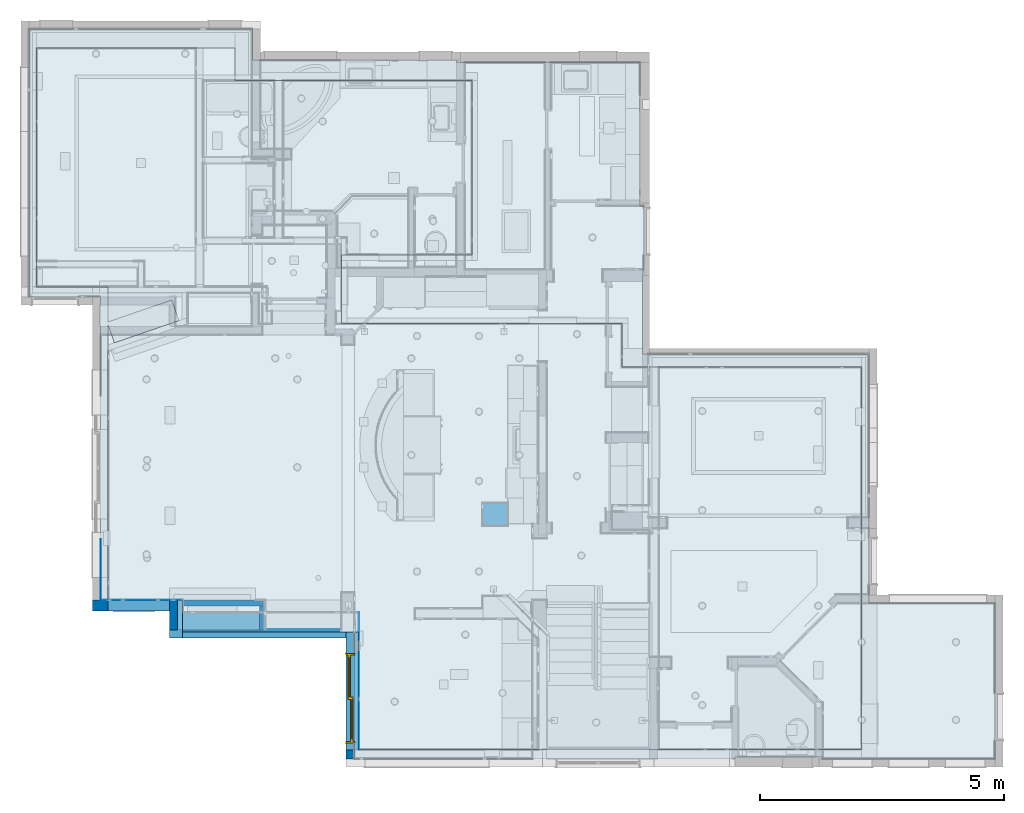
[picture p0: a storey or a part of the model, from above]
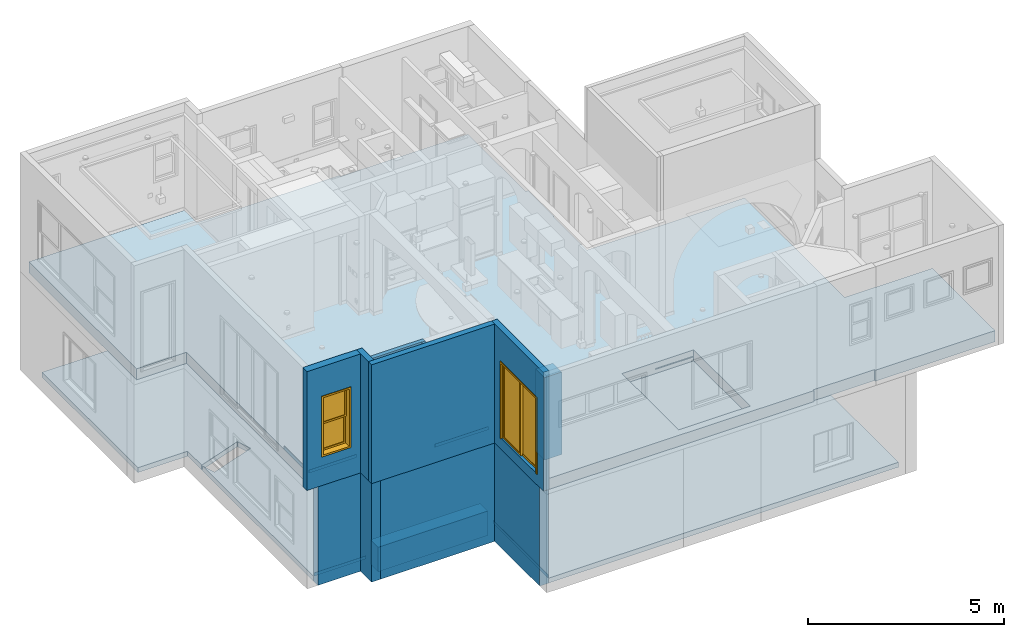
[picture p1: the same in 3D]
Properties of the parts of a building model (IFC2X3), part 1 of 2

# File
Description: ViewDefinition [CoordinationView_V2.0], RevitIdentifiers [ContentGUID: , VersionGUID: 23c3c518-4028-4475-b060-c0a772637db6, NumberOfSaves: 229], CoordinateReference [CoordinateBase: Shared Coordinates, ProjectSite: Internal]
File name: Global_Backcountry.ifc
Time: 2026-02-05T12:27:19+05:30
Written by: ODA SDAI 22.12
Made in: Autodesk Revit 23.1.80.30 (ENG) - IFC 23.4.1.0

# IfcProject, Project Number
LongName: Project Name; Phase: Project Status

# IfcSite, Default
RefLatitude: 42, 21, 30, 344238; RefLongitude: -71, -3, -35, -194702; RefElevation: 0 ft

# IfcBuilding
Pset_BuildingCommon - NumberOfStoreys: 1

# IfcBuildingStorey: Level:1/4" Head (2)
Pset_AirSideSystemInformation - sets with these values: 2
Name | LongName = Name | Elevation (ft)
First floor | First floor | 0
Third floor | Third floor | 27.1667

# IfcBuildingElementProxy: C_ Oven-Single1:C_ Oven-Single 2, C_ Oven-Single1:C_ Oven-Single 2:1988304
In: First floor
Type - Material: Default New Material
Classification: E1090320 Food Service - Appliances & Equipment (Uniformat)
Pset_BuildingElementProxyCommon - Reference: C_ Oven-Single 2; sets with these values: 2

# IfcBuildingElementProxy: C_ Oven-Single1:C_ Oven-Single 3, C_ Oven-Single1:C_ Oven-Single 3:1993433
In: First floor
Type - Material: Default New Material
Classification: E1090320 Food Service - Appliances & Equipment (Uniformat)
Pset_BuildingElementProxyCommon - Reference: C_ Oven-Single 3; sets with these values: 2

# IfcBuildingElementProxy: C_Ceiling Plinth:C_Ceiling Plinth (19)
In: First floor
Type - Material: Default New Material
Pset_BuildingElementProxyCommon - Reference: C_Ceiling Plinth; sets with these values: 2
Name (C_Ceiling Plinth:C_Ceiling Plinth:...)
1970175
1970182
1970189
1970195
1970569
1970576
1970590
1970596
1973254
1973261
1973268
1973275
1973369
1973376
1973383
1973389
1978767
1978790
2012152

# IfcBuildingElementProxy: C_Kitchen Hood:C_Kitchen Hood 2, C_Kitchen Hood:C_Kitchen Hood 2:1905955
In: First floor
Type - Material: Default New Material
Classification: E1090320 Food Service - Appliances & Equipment (Uniformat)
Pset_BuildingElementProxyCommon - Reference: C_Kitchen Hood 2; sets with these values: 2

# IfcBuildingElementProxy: C_Oven-Microwave1:C_Oven-Microwave 2, C_Oven-Microwave1:C_Oven-Microwave 2:1991351
In: First floor
Type - Material: Default New Material
Classification: E1090320 Food Service - Appliances & Equipment (Uniformat)
Pset_BuildingElementProxyCommon - Reference: C_Oven-Microwave 2; sets with these values: 2

# IfcBuildingElementProxy: C_Refrigerator:30" x 24" LH, C_Refrigerator:30" x 24" LH:1872095
In: First floor
Type - Material: Default New Material, Metal - Chrome
Classification: E1090400 Residential Equipment (Uniformat)
Pset_BuildingElementProxyCommon - Reference: 30" x 24" LH; sets with these values: 2

# IfcBuildingElementProxy: C_Wall Board:C_Wall Board (6)
In: First floor
Type - Material: Default New Material
Pset_BuildingElementProxyCommon - Reference: C_Wall Board; sets with these values: 2
Name (C_Wall Board:C_Wall Board:...)
1997285
1997406
1997414
1997422
1997430
1997438

# IfcBuildingElementProxy: Generic Models 10:Generic Models 10, Generic Models 10:Generic Models 10:1850394
In: First floor
Type - Material: Default New Material
Pset_BuildingElementProxyCommon - Reference: Generic Models 10; sets with these values: 2

# IfcBuildingElementProxy: Generic Models 11:Generic Models 11, Generic Models 11:Generic Models 11:1826560
In: First floor
Type - Material: Default New Material
Pset_BuildingElementProxyCommon - Reference: Generic Models 11; sets with these values: 2

# IfcBuildingElementProxy: Generic Models 14:Generic Models 14, Generic Models 14:Generic Models 14:2007178
In: First floor
Type - Material: Default New Material
Pset_BuildingElementProxyCommon - Reference: Generic Models 14; sets with these values: 2

# IfcBuildingElementProxy: Generic Models 15:Generic Models 4, Generic Models 15:Generic Models 4:1890981
In: First floor
Type - Material: Default New Material
Pset_BuildingElementProxyCommon - Reference: Generic Models 4; sets with these values: 2

# IfcBuildingElementProxy: Generic Models 16:Generic Models 16, Generic Models 16:Generic Models 16:1832114
In: First floor
Type - Material: Default New Material, Glass
Pset_BuildingElementProxyCommon - Reference: Generic Models 16; sets with these values: 2

# IfcBuildingElementProxy: Generic Models 18:Generic Models 18, Generic Models 18:Generic Models 18:2007954
In: First floor
Type - Material: Default New Material
Pset_BuildingElementProxyCommon - Reference: Generic Models 18; sets with these values: 2

# IfcBuildingElementProxy: Generic Models 22:Generic Models 22, Generic Models 22:Generic Models 22:1832233
In: First floor
Type - Material: Default New Material
Pset_BuildingElementProxyCommon - Reference: Generic Models 22; sets with these values: 2

# IfcBuildingElementProxy: Generic Models 23:Generic Models 16, Generic Models 23:Generic Models 16:1821259
In: First floor
Type - Material: Default New Material
Pset_BuildingElementProxyCommon - Reference: Generic Models 16; sets with these values: 2

# IfcBuildingElementProxy: Generic Models 24:Generic Models 24, Generic Models 24:Generic Models 24:1832501
In: First floor
Type - Material: Default New Material
Pset_BuildingElementProxyCommon - Reference: Generic Models 24; sets with these values: 2

# IfcBuildingElementProxy: Generic Models 25:Generic Models 23, Generic Models 25:Generic Models 23:1834578
In: First floor
Type - Material: Default New Material
Pset_BuildingElementProxyCommon - Reference: Generic Models 23; sets with these values: 2

# IfcBuildingElementProxy: Generic Models 30:Generic Models 30, Generic Models 30:Generic Models 30:2006890
In: First floor
Type - Material: Default New Material
Pset_BuildingElementProxyCommon - Reference: Generic Models 30; sets with these values: 2

# IfcBuildingElementProxy: Generic Models 38:Generic Models 38, Generic Models 38:Generic Models 38:1893735
In: First floor
Type - Material: Default New Material
Pset_BuildingElementProxyCommon - Reference: Generic Models 38; sets with these values: 2

# IfcBuildingElementProxy: Generic Models 4:Generic Models 3, Generic Models 4:Generic Models 3:1832471
In: First floor
Type - Material: Glass
Pset_BuildingElementProxyCommon - Reference: Generic Models 3; sets with these values: 2

# IfcBuildingElementProxy: Generic Models 52:Generic Models 52, Generic Models 52:Generic Models 52:1856574
In: First floor
Type - Material: Default New Material
Pset_BuildingElementProxyCommon - Reference: Generic Models 52; sets with these values: 2

# IfcBuildingElementProxy: Generic Models 59:Generic Models 59, Generic Models 59:Generic Models 59:1832529
In: First floor
Type - Material: Default New Material
Pset_BuildingElementProxyCommon - Reference: Generic Models 59; sets with these values: 2

# IfcBuildingElementProxy: Generic Models 60:Generic Models 59, Generic Models 60:Generic Models 59:1832543
In: First floor
Type - Material: Default New Material
Pset_BuildingElementProxyCommon - Reference: Generic Models 59; sets with these values: 2

# IfcBuildingElementProxy: Generic Models 61:Generic Models 61, Generic Models 61:Generic Models 61:1834870
In: First floor
Type - Material: Default New Material
Pset_BuildingElementProxyCommon - Reference: Generic Models 61; sets with these values: 2

# IfcBuildingElementProxy: Generic Models 66:Generic Models 66, Generic Models 66:Generic Models 66:1836599
In: First floor
Type - Material: Default New Material
Pset_BuildingElementProxyCommon - Reference: Generic Models 66; sets with these values: 2

# IfcBuildingElementProxy: Generic Models 67:Generic Models 67, Generic Models 67:Generic Models 67:1890026
In: First floor
Type - Material: Default New Material
Pset_BuildingElementProxyCommon - Reference: Generic Models 67; sets with these values: 2

# IfcBuildingElementProxy: Generic Models 68:Generic Models 68, Generic Models 68:Generic Models 68:1878332
In: First floor
Type - Material: Default New Material
Pset_BuildingElementProxyCommon - Reference: Generic Models 68; sets with these values: 2

# IfcBuildingElementProxy: Generic Models 7:Generic Models 7, Generic Models 7:Generic Models 7:1826515
In: First floor
Type - Material: Default New Material
Pset_BuildingElementProxyCommon - Reference: Generic Models 7; sets with these values: 2

# IfcBuildingElementProxy: Generic Models 8:Generic Models 8, Generic Models 8:Generic Models 8:1850366
In: First floor
Type - Material: Default New Material
Pset_BuildingElementProxyCommon - Reference: Generic Models 8; sets with these values: 2

# IfcBuildingElementProxy: Generic Models 9:Generic Models 9, Generic Models 9:Generic Models 9:1850380
In: First floor
Type - Material: Default New Material
Pset_BuildingElementProxyCommon - Reference: Generic Models 9; sets with these values: 2

# IfcBuildingElementProxy: Specialty Equipment 1:Specialty Equipment 1, Specialty Equipment 1:Specialty Equipment 1:1830147
In: First floor
Type - Material: Default New Material
Pset_BuildingElementProxyCommon - Reference: Specialty Equipment 1; sets with these values: 2

# IfcBuildingElementProxy: Specialty Equipment_1:Specialty Equipment_1 (10)
In: First floor
Type - Material: Default New Material
Pset_BuildingElementProxyCommon - Reference: Specialty Equipment_1; sets with these values: 2
Name (Specialty Equipment_1:Specialty Equipment_1:...)
1832861
1832868
1832869
1832870
1832871
1832872
1832873
1832874
1832875
1832876

# IfcBuildingElementProxy: Specialty Equipment_2:Specialty Equipment_2, Specialty Equipment_2:Specialty Equipment_2:1875328
In: First floor
Type - Material: Default New Material
Pset_BuildingElementProxyCommon - Reference: Specialty Equipment_2; sets with these values: 2

# IfcBuildingElementProxy: Specialty Equipment_4:Specialty Equipment_4 (6)
In: First floor
Type - Material: Default New Material
Pset_BuildingElementProxyCommon - Reference: Specialty Equipment_4; sets with these values: 2
Name (Specialty Equipment_4:Specialty Equipment_4:...)
1834781
1834782
1834783
1834784
1834785
1834786

# IfcBuildingElementProxy: Wall void 1 :Wall void 1, Wall void 1 :Wall void 1:1623852
In: First floor
Type - Material: Default New Material
Pset_BuildingElementProxyCommon - Reference: Wall void 1; sets with these values: 2

# IfcBuildingElementProxy: switch 15:switch 15 (9)
In: First floor
Type - Material: Default New Material
Pset_BuildingElementProxyCommon - Reference: switch 15; sets with these values: 2
Name (switch 15:switch 15:...)
1977471
1978495
1978551
1980305
1980369
1980450
1999142
1999231
1999335

# IfcBuildingElementProxy: switch 1:switch 1 (35)
In: First floor
Type - Material: Default New Material
Pset_BuildingElementProxyCommon - Reference: switch 1; sets with these values: 2
Name (switch 1:switch 1:...)
1818208
1818322
1830585
1830647
1833578
1833643
1835219
1835559
1836760
1844375
1849006
1849609
1849780
1854866
1854953
1856204
1863419
1863629
1863692
1866938
1867050
1890236
1890352
1890636
1893331
1898502
1898551
1898586
1898853
1900308
1900660
1900951
1901115
1902148
1902609

# IfcBuildingElementProxy: switch 20:switch 20, switch 20:switch 20:1898083
In: First floor
Type - Material: Default New Material
Pset_BuildingElementProxyCommon - Reference: switch 20; sets with these values: 2

# IfcBuildingElementProxy: switch 22:switch 22 (8)
In: First floor
Type - Material: Default New Material
Pset_BuildingElementProxyCommon - Reference: switch 22; sets with these values: 2
Name (switch 22:switch 22:...)
1829911
1833335
1836847
1857173
1861944
1863794
1878393
1899789

# IfcBuildingElementProxy: switch 24:switch 24 (4)
In: First floor
Type - Material: Default New Material
Pset_BuildingElementProxyCommon - Reference: switch 24; sets with these values: 2
Name (switch 24:switch 24:...)
1862058
1862175
1867309
1868340

# IfcBuildingElementProxy: switch 2:switch 2 (2)
In: First floor
Type - Material: Default New Material
Pset_BuildingElementProxyCommon - Reference: switch 2; sets with these values: 2
Name (switch 2:switch 2:...)
1890583
1890810

# IfcBuildingElementProxy: switch 3:switch 3 (10)
In: First floor
Type - Material: Default New Material
Pset_BuildingElementProxyCommon - Reference: switch 3; sets with these values: 2
Name (switch 3:switch 3:...)
1826171
1830789
1835476
1855795
1883014
1887228
1899510
1900826
1902023
1902519

# IfcBuildingElementProxy: switch 4:switch 4 (50)
In: First floor
Type - Material: Default New Material
Pset_BuildingElementProxyCommon - Reference: switch 4; sets with these values: 2
Name (switch 4:switch 4:...)
1818084
1818843
1825703
1830070
1832985
1833240
1833453
1833995
1834143
1835044
1836454
1836673
1844247
1849133
1856108
1861414
1862980
1863063
1863317
1864811
1864893
1883154
1888046
1890142
1890323
1890444
1890517
1890704
1892060
1892179
1893450
1893569
1893621
1893776
1893854
1898173
1899133
1899192
1899691
1899955
1900022
1900478
1900567
1901199
1901303
1901771
1901831
1901936
1902272
2013332

# IfcBuildingElementProxy: switch 6:switch 6 (14)
In: First floor
Type - Material: Default New Material
Pset_BuildingElementProxyCommon - Reference: switch 6; sets with these values: 2
Name (switch 6:switch 6:...)
1818533
1818772
1833104
1833717
1833870
1837094
1837330
1855957
1866779
1888173
1889682
1900150
1905417
1917963

# IfcColumn: M_Rectangular Column:475 x 610mm, M_Rectangular Column:475 x 610mm:2013331
In: First floor
Type - PredefinedType: COLUMN; Material: Default New Material
Pset_ColumnCommon - IsExternal: no; Reference: 475 x 610mm
Pset_QuantityTakeOff - Reference: 475 x 610mm; sets with these values: 2

# IfcCovering: Compound Ceiling:Ceiling_1.5", Compound Ceiling:Ceiling_1.5":1623691
In: First floor
Type - PredefinedType: CEILING
Type - Pset_CoveringCommon - TotalThickness: 0.125 ft
Classification: C3030210 Suspended Ceilings - Acoustical (Uniformat); Material: Default New Material 0.125 ft
Pset_CoveringCommon - Reference: Ceiling_1.5"; sets with these values: 2

# IfcCovering: Compound Ceiling:Ceiling_1.5" 1, Compound Ceiling:Ceiling_1.5" 1:1623705
In: First floor
Type - PredefinedType: CEILING
Type - Pset_CoveringCommon - TotalThickness: 0.125 ft
Classification: C3030210 Suspended Ceilings - Acoustical (Uniformat); Material: Default New Material 0.125 ft
Pset_CoveringCommon - Reference: Ceiling_1.5" 1; sets with these values: 2

# IfcCovering: Compound Ceiling:Ceiling_12", Compound Ceiling:Ceiling_12":1623663
In: First floor
Type - PredefinedType: CEILING
Type - Pset_CoveringCommon - TotalThickness: 1 ft
Classification: C3030210 Suspended Ceilings - Acoustical (Uniformat); Material: Default New Material 1 ft
Pset_CoveringCommon - Reference: Ceiling_12"; sets with these values: 2

# IfcCovering: Compound Ceiling:Ceiling_13.5", Compound Ceiling:Ceiling_13.5":1623320
In: First floor
Type - PredefinedType: CEILING
Type - Pset_CoveringCommon - TotalThickness: 1.125 ft
Classification: C3030210 Suspended Ceilings - Acoustical (Uniformat); Material: Default New Material 1.125 ft
Pset_CoveringCommon - Reference: Ceiling_13.5"; sets with these values: 2

# IfcCovering: Compound Ceiling:Ceiling_14", Compound Ceiling:Ceiling_14":1623614
In: First floor
Type - PredefinedType: CEILING
Type - Pset_CoveringCommon - TotalThickness: 1.16667 ft
Classification: C3030210 Suspended Ceilings - Acoustical (Uniformat); Material: Default New Material 1.16667 ft
Pset_CoveringCommon - Reference: Ceiling_14"; sets with these values: 2

# IfcCovering: Compound Ceiling:Ceiling_2", Compound Ceiling:Ceiling_2":1623593
In: First floor
Type - PredefinedType: CEILING
Type - Pset_CoveringCommon - TotalThickness: 0.166667 ft
Classification: C3030210 Suspended Ceilings - Acoustical (Uniformat); Material: Default New Material 0.166667 ft
Pset_CoveringCommon - Reference: Ceiling_2"; sets with these values: 2

# IfcCovering: Compound Ceiling:Ceiling_5.25", Compound Ceiling:Ceiling_5.25":1623642
In: First floor
Type - PredefinedType: CEILING
Type - Pset_CoveringCommon - TotalThickness: 0.4375 ft
Classification: C3030210 Suspended Ceilings - Acoustical (Uniformat); Material: Default New Material 0.4375 ft
Pset_CoveringCommon - Reference: Ceiling_5.25"; sets with these values: 2

# IfcCovering: Compound Ceiling:Ceiling_6" (6)
In: First floor
Type - PredefinedType: CEILING
Type - Pset_CoveringCommon - TotalThickness: 0.5 ft
Classification: C3030210 Suspended Ceilings - Acoustical (Uniformat); Material: Default New Material 0.5 ft
Pset_CoveringCommon - Reference: Ceiling_6"; sets with these values: 2
Name (Compound Ceiling:Ceiling_6":...)
1623496
1623539
1623550
1843769
1878108
1887144

# IfcDistributionPort (54)
Description: Flow; FlowDirection: SOURCEANDSINK
Name
Port_1757719_1
Port_1759716_1
Port_1759780_1
Port_1759781_1
Port_1759806_1
Port_1759857_1
Port_1760309_1
Port_1760412_1
Port_1760436_1
Port_1760555_1
Port_1760695_1
Port_1760920_1
Port_1760941_1
Port_1760962_1
Port_1761019_1
Port_1761040_1
Port_1761170_1
Port_1761231_1
Port_1761579_1
Port_1761622_1
Port_1761695_1
Port_1761776_1
Port_1761873_1
Port_1761934_1
Port_1762098_1
Port_1764306_1
Port_1764405_1
Port_1764552_1
Port_1764702_1
Port_1764775_1
Port_1764865_1
Port_1764925_1
Port_1764992_1
Port_1765164_1
Port_1765362_1
Port_1765494_1
Port_1765568_1
Port_1765795_1
Port_1765961_1
Port_1766023_1
Port_1766063_1
Port_1766123_1
Port_1766230_1
Port_1766277_1
Port_1766412_1
Port_1766564_1
Port_1766834_1
Port_1766973_1
Port_1767096_1
Port_1767216_1
Port_1767358_1
Port_1988304_1
Port_1991351_1
Port_1993433_1

# IfcDoor: C_Double Door Glass:4'-8" X 8'-0", C_Double Door Glass:4'-8" X 8'-0":1623472
In: First floor
Type - OperationType: DOUBLE_DOOR_SINGLE_SWING_OPPOSITE_RIGHT; ParameterTakesPrecedence: no; Sizeable: no; Material: Default New Material, Glass
Type - C_Double Door Glass:4'-8" X 8'-0":1623472:1 - PanelOperation: SWINGING
OverallHeight: 8.08333 ft; OverallWidth: 4.83333 ft
Pset_DoorCommon - Reference: 4'-8" X 8'-0"; IsExternal: no
Pset_QuantityTakeOff - Reference: 4'-8" X 8'-0"

# IfcDoor: C_Double Door Glass:4'-8" X 8'-2", C_Double Door Glass:4'-8" X 8'-2":1623377
In: First floor
Type - OperationType: DOUBLE_DOOR_SINGLE_SWING_OPPOSITE_LEFT; ParameterTakesPrecedence: no; Sizeable: no; Material: Default New Material, Glass
Type - C_Double Door Glass:4'-8" X 8'-2":1623377:1 - PanelOperation: SWINGING
OverallHeight: 8.25 ft; OverallWidth: 4.83333 ft
Pset_DoorCommon - IsExternal: no; Reference: 4'-8" X 8'-2"
Pset_QuantityTakeOff - Reference: 4'-8" X 8'-2"

# IfcDoor: C_Single Door Glass:3'-0" X 8'-0", C_Single Door Glass:3'-0" X 8'-0":1623399
In: First floor
Type - OperationType: SINGLE_SWING_RIGHT; ParameterTakesPrecedence: no; Sizeable: no; Material: Glass, Default New Material
Type - C_Single Door Glass:3'-0" X 8'-0":1623399:1 - PanelOperation: SWINGING
OverallHeight: 8.08333 ft; OverallWidth: 3.16667 ft
Pset_DoorCommon - IsExternal: no; Reference: 3'-0" X 8'-0"
Pset_QuantityTakeOff - Reference: 3'-0" X 8'-0"

# IfcDoor: C_Single Door Glass:3'-0" X 8'-0", C_Single Door Glass:3'-0" X 8'-0":1623471
In: First floor
Type - OperationType: SINGLE_SWING_RIGHT; ParameterTakesPrecedence: no; Sizeable: no; Material: Glass, Default New Material
Type - C_Single Door Glass:3'-0" X 8'-0":1623471:1 - PanelOperation: SWINGING
OverallHeight: 8.08333 ft; OverallWidth: 3.16667 ft
Pset_DoorCommon - IsExternal: no; Reference: 3'-0" X 8'-0"
Pset_QuantityTakeOff - Reference: 3'-0" X 8'-0"

# IfcDoor: C_Single Door:2'-0" X 8'-0", C_Single Door:2'-0" X 8'-0":1623488
In: First floor
Type - OperationType: SINGLE_SWING_LEFT; ParameterTakesPrecedence: no; Sizeable: no; Material: Default New Material
Type - C_Single Door:2'-0" X 8'-0":1623488:1 - PanelOperation: SWINGING
OverallHeight: 8.08333 ft; OverallWidth: 2.16667 ft
Pset_DoorCommon - Reference: 2'-0" X 8'-0"; IsExternal: no
Pset_QuantityTakeOff - Reference: 2'-0" X 8'-0"

# IfcDoor: C_Single Door:2'-4" X 8'-0" (4)
In: First floor
Type - OperationType: SINGLE_SWING_RIGHT; ParameterTakesPrecedence: no; Sizeable: no; Material: Default New Material
Type - C_Single Door:2'-4" X 8'-0":1623375:1 - PanelOperation: SWINGING
OverallHeight: 8.08333 ft; OverallWidth: 2.5 ft
Pset_DoorCommon - IsExternal: no; Reference: 2'-4" X 8'-0"
Pset_QuantityTakeOff - Reference: 2'-4" X 8'-0"
Name (C_Single Door:2'-4" X 8'-0":...)
1623375
1623376
1623473
1623474

# IfcDoor: C_Single Door:2'-4" X 8'-0", C_Single Door:2'-4" X 8'-0":1623401
In: First floor
Type - OperationType: SINGLE_SWING_RIGHT; ParameterTakesPrecedence: no; Sizeable: no; Material: Default New Material
Type - C_Single Door:2'-4" X 8'-0":1623401:1 - PanelOperation: SWINGING
OverallHeight: 8.08333 ft; OverallWidth: 2.5 ft
Pset_DoorCommon - IsExternal: no; Reference: 2'-4" X 8'-0"
Pset_QuantityTakeOff - Reference: 2'-4" X 8'-0"

# IfcDoor: C_Single Door:2'-4" X 8'-2", C_Single Door:2'-4" X 8'-2":1623386
In: First floor
Type - OperationType: SINGLE_SWING_LEFT; ParameterTakesPrecedence: no; Sizeable: no; Material: Default New Material
Type - C_Single Door:2'-4" X 8'-2":1623386:1 - PanelOperation: SWINGING
OverallHeight: 8.25 ft; OverallWidth: 2.5 ft
Pset_DoorCommon - IsExternal: no; Reference: 2'-4" X 8'-2"
Pset_QuantityTakeOff - Reference: 2'-4" X 8'-2"

# IfcDoor: C_Single Door:2'-4" X 8'-2" (3)
In: First floor
Type - OperationType: SINGLE_SWING_RIGHT; ParameterTakesPrecedence: no; Sizeable: no; Material: Default New Material
Type - C_Single Door:2'-4" X 8'-2":1623384:1 - PanelOperation: SWINGING
OverallHeight: 8.25 ft; OverallWidth: 2.5 ft
Pset_DoorCommon - IsExternal: no; Reference: 2'-4" X 8'-2"
Pset_QuantityTakeOff - Reference: 2'-4" X 8'-2"
Name (C_Single Door:2'-4" X 8'-2":...)
1623384
1623387
1623388

# IfcDoor: C_Single Door:2'-6" X 6'-8", C_Single Door:2'-6" X 6'-8":1623378
In: First floor
Type - OperationType: SINGLE_SWING_LEFT; ParameterTakesPrecedence: no; Sizeable: no; Material: Default New Material
Type - C_Single Door:2'-6" X 6'-8":1623378:1 - PanelOperation: SWINGING
OverallHeight: 6.75 ft; OverallWidth: 2.66667 ft
Pset_DoorCommon - IsExternal: no; Reference: 2'-6" X 6'-8"
Pset_QuantityTakeOff - Reference: 2'-6" X 6'-8"

# IfcDoor: C_Single Door:2'-6" X 8'-0" (2)
In: First floor
Type - OperationType: SINGLE_SWING_LEFT; ParameterTakesPrecedence: no; Sizeable: no; Material: Default New Material
Type - C_Single Door:2'-6" X 8'-0":1623370:1 - PanelOperation: SWINGING
OverallHeight: 8.08333 ft; OverallWidth: 2.66667 ft
Pset_DoorCommon - IsExternal: no; Reference: 2'-6" X 8'-0"
Pset_QuantityTakeOff - Reference: 2'-6" X 8'-0"
Name (C_Single Door:2'-6" X 8'-0":...)
1623370
1623380

# IfcDoor: C_Single Door:2'-6" X 8'-0", C_Single Door:2'-6" X 8'-0":1623374
In: First floor
Type - OperationType: SINGLE_SWING_LEFT; ParameterTakesPrecedence: no; Sizeable: no; Material: Default New Material
Type - C_Single Door:2'-6" X 8'-0":1623374:1 - PanelOperation: SWINGING
OverallHeight: 8.08333 ft; OverallWidth: 2.66667 ft
Pset_DoorCommon - IsExternal: no; Reference: 2'-6" X 8'-0"
Pset_QuantityTakeOff - Reference: 2'-6" X 8'-0"

# IfcDoor: C_Single Door:2'-6" X 8'-0", C_Single Door:2'-6" X 8'-0":1623393
In: First floor
Type - OperationType: SINGLE_SWING_LEFT; ParameterTakesPrecedence: no; Sizeable: no; Material: Default New Material
Type - C_Single Door:2'-6" X 8'-0":1623393:1 - PanelOperation: SWINGING
OverallHeight: 8.08333 ft; OverallWidth: 2.66667 ft
Pset_DoorCommon - IsExternal: no; Reference: 2'-6" X 8'-0"
Pset_QuantityTakeOff - Reference: 2'-6" X 8'-0"

# IfcDoor: C_Single Door:2'-6" X 8'-2", C_Single Door:2'-6" X 8'-2":1623385
In: First floor
Type - OperationType: SINGLE_SWING_RIGHT; ParameterTakesPrecedence: no; Sizeable: no; Material: Default New Material
Type - C_Single Door:2'-6" X 8'-2":1623385:1 - PanelOperation: SWINGING
OverallHeight: 8.25 ft; OverallWidth: 2.66667 ft
Pset_DoorCommon - IsExternal: no; Reference: 2'-6" X 8'-2"
Pset_QuantityTakeOff - Reference: 2'-6" X 8'-2"

# IfcDoor: C_Single Door:2'-6" X 8'-2", C_Single Door:2'-6" X 8'-2":1623390
In: First floor
Type - OperationType: SINGLE_SWING_RIGHT; ParameterTakesPrecedence: no; Sizeable: no; Material: Default New Material
Type - C_Single Door:2'-6" X 8'-2":1623390:1 - PanelOperation: SWINGING
OverallHeight: 8.25 ft; OverallWidth: 2.66667 ft
Pset_DoorCommon - IsExternal: no; Reference: 2'-6" X 8'-2"
Pset_QuantityTakeOff - Reference: 2'-6" X 8'-2"

# IfcDoor: C_Single Door:2'-8" X 8'-0", C_Single Door:2'-8" X 8'-0":1623371
In: First floor
Type - OperationType: SINGLE_SWING_RIGHT; ParameterTakesPrecedence: no; Sizeable: no; Material: Default New Material
Type - C_Single Door:2'-8" X 8'-0":1623371:1 - PanelOperation: SWINGING
OverallHeight: 8.08333 ft; OverallWidth: 2.83333 ft
Pset_DoorCommon - IsExternal: no; Reference: 2'-8" X 8'-0"
Pset_QuantityTakeOff - Reference: 2'-8" X 8'-0"

# IfcDoor: C_Single Door:3'-0" X 8'-0" (3)
In: First floor
Type - OperationType: SINGLE_SWING_LEFT; ParameterTakesPrecedence: no; Sizeable: no; Material: Default New Material
Type - C_Single Door:3'-0" X 8'-0":1623373:1 - PanelOperation: SWINGING
OverallHeight: 8.08333 ft; OverallWidth: 3.16667 ft
Pset_DoorCommon - IsExternal: no; Reference: 3'-0" X 8'-0"
Pset_QuantityTakeOff - Reference: 3'-0" X 8'-0"
Name (C_Single Door:3'-0" X 8'-0":...)
1623373
1623379
1623400

# IfcDoor: C_Single Door:3'-0" X 8'-0", C_Single Door:3'-0" X 8'-0":1623476
In: First floor
Type - OperationType: SINGLE_SWING_RIGHT; ParameterTakesPrecedence: no; Sizeable: no; Material: Default New Material
Type - C_Single Door:3'-0" X 8'-0":1623476:1 - PanelOperation: SWINGING
OverallHeight: 8.08333 ft; OverallWidth: 3.16667 ft
Pset_DoorCommon - IsExternal: no; Reference: 3'-0" X 8'-0"
Pset_QuantityTakeOff - Reference: 3'-0" X 8'-0"

# IfcDoor: C_Sliding Door Double Glass:5'-10" X 7'-8", C_Sliding Door Double Glass:5'-10" X 7'-8":1623487
In: First floor
Type - ParameterTakesPrecedence: no; Sizeable: no; Material: Default New Material, Glass
OverallHeight: 7.75 ft; OverallWidth: 6 ft
Pset_DoorCommon - IsExternal: no; Reference: 5'-10" X 7'-8"
Pset_QuantityTakeOff - Reference: 5'-10" X 7'-8"

# IfcDoor: C_Sliding Door Double:4'-10" X 8'-0", C_Sliding Door Double:4'-10" X 8'-0":1623391
In: First floor
Type - ParameterTakesPrecedence: no; Sizeable: no; Material: Default New Material
OverallHeight: 8.08333 ft; OverallWidth: 5 ft
Pset_DoorCommon - IsExternal: no; Reference: 4'-10" X 8'-0"
Pset_QuantityTakeOff - Reference: 4'-10" X 8'-0"

# IfcDoor: Double Sliding Door:9'-4" X 7'-10", Double Sliding Door:9'-4" X 7'-10":1623853
In: First floor
Type - ParameterTakesPrecedence: no; Sizeable: no; Material: Glass, Default New Material
OverallHeight: 7.91667 ft; OverallWidth: 9.5 ft
Pset_DoorCommon - IsExternal: no; Reference: 9'-4" X 7'-10"
Pset_QuantityTakeOff - Reference: 9'-4" X 7'-10"

# IfcFlowTerminal: C_Bathtub:C_Bathtub 2, C_Bathtub:C_Bathtub 2:1904748
In: First floor
Type - Material: Default New Material
Pset_DistributionFlowElementCommon - Reference: C_Bathtub 2; sets with these values: 2

# IfcFlowTerminal: C_Ceiling Lamp:C_Ceiling Lamp (9)
In: First floor
Type - Material: Default New Material
Pset_DistributionFlowElementCommon - Reference: C_Ceiling Lamp; sets with these values: 2
Name (C_Ceiling Lamp:C_Ceiling Lamp:...)
1826880
1837242
1843854
1861611
1861679
1861702
1861727
1861754
1878204

# IfcFlowTerminal: C_Ceiling Light Rectangular Flushed:Light 9, C_Ceiling Light Rectangular Flushed:Light 9:1884129
In: First floor
Type - Material: Default New Material, Glass
Pset_DistributionFlowElementCommon - Reference: Light 9; sets with these values: 2

# IfcFlowTerminal: C_Ceiling Light Rectangular Recessed:Light 12, C_Ceiling Light Rectangular Recessed:Light 12:1883856
In: First floor
Type - Material: Glass, Default New Material
Pset_DistributionFlowElementCommon - Reference: Light 12; sets with these values: 2

# IfcFlowTerminal: C_Dishwasher:24"x25 1/4", C_Dishwasher:24"x25 1/4":1738830
In: First floor
Type - Material: Default New Material
Type - Pset_ElectricalDeviceCommon - NumberOfPoles: 1
Pset_DistributionFlowElementCommon - Reference: 24"x25 1/4"; sets with these values: 2

# IfcFlowTerminal: C_Grill_Surface Based:Standard 2 (25)
In: First floor
Type - Material: Default New Material
Pset_DistributionFlowElementCommon - Reference: Standard 2; sets with these values: 2
Name (C_Grill_Surface Based:Standard 2:...)
1821344
1836185
1844489
1855375
1856365
1856762
1862669
1863134
1878629
1878930
1883320
1884052
1891436
1891703
1892282
1892369
1892424
1892573
1892649
1892716
1901380
2004932
2005081
2005169
2008913

# IfcFlowTerminal: C_Kitchen Sink Single:C_Kitchen Sink Single (3)
In: First floor
Type - Material: Default New Material
Pset_DistributionFlowElementCommon - Reference: C_Kitchen Sink Single; sets with these values: 2
Name (C_Kitchen Sink Single:C_Kitchen Sink Single:...)
2012840
2013835
2013907

# IfcFlowTerminal: C_Kitchen Sink Single:C_Kitchen Sink Single 3, C_Kitchen Sink Single:C_Kitchen Sink Single 3:2008436
In: First floor
Type - Material: Default New Material
Pset_DistributionFlowElementCommon - Reference: C_Kitchen Sink Single 3; sets with these values: 2

# IfcFlowTerminal: C_Kitchen Sink Single:C_Kitchen Sink Single 4, C_Kitchen Sink Single:C_Kitchen Sink Single 4:2005322
In: First floor
Type - Material: Default New Material
Pset_DistributionFlowElementCommon - Reference: C_Kitchen Sink Single 4; sets with these values: 2

# IfcFlowTerminal: C_Sconce Downwards:33700 ICARIA White ceiling fan / Wood Blade (7)
In: First floor
Type - Material: Default New Material
Type - Pset_ManufacturerTypeInformation - Manufacturer: FARO Barcelona
Pset_DistributionFlowElementCommon - Reference: 33700 ICARIA White ceiling fan / Wood Blade; sets with these values: 2
Name (C_Sconce Downwards:33700 ICARIA White ceiling fan / Wood Blade:...)
1976925
1977011
1977112
1977184
1977224
1982164
2006386

# IfcFlowTerminal: C_Spotlight Recessed:Light 2 (51)
In: First floor
Type - Material: Default New Material, Glass, White, High Luminance
Type - Pset_ElectricalDeviceCommon - NumberOfPoles: 1
Pset_DistributionFlowElementCommon - Reference: Light 2; sets with these values: 2
Name (C_Spotlight Recessed:Light 2:...)
1757719
1759716
1759780
1759781
1759806
1759857
1760309
1760412
1760436
1760555
1760695
1760920
1760941
1760962
1761019
1761040
1761170
1761231
1761579
1761622
1761695
1761776
1761873
1761934
1762098
1764306
1764405
1764552
1764702
1764775
1764865
1764925
1764992
1765164
1765362
1765494
1765568
1765795
1765961
1766023
1766063
1766123
1766230
1766277
1766412
1766564
1766834
1766973
1767096
1767216
1767358

# IfcFlowTerminal: C_Toilet Basin:Plumbing Fixtures 34 (3)
In: First floor
Type - Material: Default New Material
Pset_DistributionFlowElementCommon - Reference: Plumbing Fixtures 34; sets with these values: 2
Name (C_Toilet Basin:Plumbing Fixtures 34:...)
1821767
1879437
1905096

# IfcFlowTerminal: C_Wall Lamp Horizontal:C_Wall Lamp Horizontal (3)
In: First floor
Type - Material: Default New Material
Pset_DistributionFlowElementCommon - Reference: C_Wall Lamp Horizontal; sets with these values: 2
Name (C_Wall Lamp Horizontal:C_Wall Lamp Horizontal:...)
1818923
1880983
1881978

# IfcFlowTerminal: Plumbing Fixtures 7:Plumbing Fixtures 7, Plumbing Fixtures 7:Plumbing Fixtures 7:1882912
In: First floor
Type - Material: Default New Material
Pset_DistributionFlowElementCommon - Reference: Plumbing Fixtures 7; sets with these values: 2

# IfcFlowTerminal: Sink-4:Sink-4, Sink-4:Sink-4:1823152
In: First floor
Type - Material: Default New Material
Pset_DistributionFlowElementCommon - Reference: Sink-4; sets with these values: 2

# IfcFurnishingElement: C_Cabinet Module Double Door:C_Cabinet Module Double Door (28)
In: First floor
Type - Material: Default New Material
Pset_QuantityTakeOff - Reference: C_Cabinet Module Double Door
Name (C_Cabinet Module Double Door:C_Cabinet Module Double Door:...)
1731715
1731925
1732006
1732149
1732274
1732368
1732474
1732663
1732765
1732846
1736810
1736943
1858305
1858794
1873111
1875522
1875651
1879776
1879927
1880189
1883602
1883756
1883817
1887339
1888602
1903157
1980601
1998715

# IfcFurnishingElement: C_Cabinet Single Module:C_Cabinet Single Module (9)
In: First floor
Type - Material: Default New Material
Pset_QuantityTakeOff - Reference: C_Cabinet Single Module
Name (C_Cabinet Single Module:C_Cabinet Single Module:...)
1737036
1737349
1858578
1858795
1880017
1888408
1888781
1902891
1998868

# IfcFurnishingElement: C_Casework Empty:C_Casework Empty (4)
In: First floor
Type - Material: Default New Material
Pset_QuantityTakeOff - Reference: C_Casework Empty
Name (C_Casework Empty:C_Casework Empty:...)
1868696
1873240
1981380
1981548

# IfcFurnishingElement: C_Counter Top L:Counter Top, C_Counter Top L:Counter Top:1880308
In: First floor
Type - Material: Default New Material
Pset_QuantityTakeOff - Reference: Counter Top

# IfcFurnishingElement: C_Counter Top Linear (without skirting):C_Counter Top Linear (without skirting) (5)
In: First floor
Type - Material: Default New Material
Pset_QuantityTakeOff - Reference: C_Counter Top Linear (without skirting)
Name (C_Counter Top Linear (without skirting):C_Counter Top Linear (without skirting):...)
1984601
1984975
1985170
1987782
1988082

# IfcFurnishingElement: C_Counter Top Linear (without skirting)_1:C_Counter Top Linear (without skirting), C_Counter Top Linear (without skirting)_1:C_Counter Top Linear (without skirting):1984759
In: First floor
Type - Material: Default New Material
Pset_QuantityTakeOff - Reference: C_Counter Top Linear (without skirting)

# IfcFurnishingElement: C_Counter Top Linear:Counter Top, C_Counter Top Linear:Counter Top:1887434
In: First floor
Type - Material: Default New Material
Pset_QuantityTakeOff - Reference: Counter Top

# IfcFurnishingElement: C_Counter Top curved:C_Counter Top curved, C_Counter Top curved:C_Counter Top curved:1986194
In: First floor
Type - Material: Default New Material
Pset_QuantityTakeOff - Reference: C_Counter Top curved

# IfcFurnishingElement: Face Based Case work:2'-6" X 1'-7", Face Based Case work:2'-6" X 1'-7":1886140
In: First floor
Type - Material: Default New Material
Pset_QuantityTakeOff - Reference: 2'-6" X 1'-7"

# IfcOpeningElement: Opening (74)
In: First floor
Name
Basic Wall:Wall_6.5":1623193:1 | Classification: B2010 Exterior Walls (Uniformat); Pset_OpeningElementCommon - Reference: Wall_6.5"; sets with these values: 2
Basic Wall:Wall_7.5":1623200 | Pset_OpeningElementCommon - Reference: Wall void 1; sets with these values: 2
Basic Wall:Wall_4.5":1623206 | Pset_OpeningElementCommon - Reference: Generic Models 22; sets with these values: 2
Basic Wall:Wall_6.5":1623208 | Pset_OpeningElementCommon - Reference: Generic Models 16; sets with these values: 2
Basic Wall:Wall_8":1623211 | Pset_OpeningElementCommon - Reference: Generic Models 58; sets with these values: 2
Basic Wall:Wall_10":1623216 | Pset_OpeningElementCommon - Reference: Generic Models 45; sets with these values: 2
Basic Wall:Wall_4.5":1623218 | Pset_OpeningElementCommon - Reference: 2'-0" X 8'-0"; sets with these values: 2
Basic Wall:Wall_8.5":1623236 | Pset_OpeningElementCommon - Reference: Generic Models 44; sets with these values: 2
Basic Wall:Wall_11":1623237 | Pset_OpeningElementCommon - Reference: Generic Models 43; sets with these values: 2
Basic Wall:Wall_11":1623237 | Pset_OpeningElementCommon - Reference: Generic Models 2; sets with these values: 2
Basic Wall:Wall_4.5":1623239 | Pset_OpeningElementCommon - Reference: Generic Models 40; sets with these values: 2
Basic Wall:Wall_4.5":1623239 | Pset_OpeningElementCommon - Reference: Generic Models 39; sets with these values: 2
Basic Wall:Wall_8.5":1623240 | Pset_OpeningElementCommon - Reference: Generic Models 41; sets with these values: 2
Basic Wall:Wall_6.75":1623245 | Pset_OpeningElementCommon - Reference: 4'-8" X 8'-0"; sets with these values: 2
Basic Wall:Wall_9":1623251 | Pset_OpeningElementCommon - Reference: Generic Models 42; sets with these values: 2
Basic Wall:Wall_4.5":1623280 | Pset_OpeningElementCommon - Reference: Generic Models 6; sets with these values: 2
Basic Wall:Wall_4.5":1623283 | Pset_OpeningElementCommon - Reference: Generic Models 4; sets with these values: 2
Basic Wall:Wall_10":1623287 | Pset_OpeningElementCommon - Reference: Generic Models 46; sets with these values: 2
Floor:Floor_13.5":1624956 | Pset_OpeningElementCommon - Reference: Floor_13.5"; sets with these values: 2
Basic Wall:Wall Border_T1:1623795 | Pset_OpeningElementCommon - Reference: 2'-0" X 8'-0"; sets with these values: 2
Basic Wall:Wall Border_T1:1623798 | Pset_OpeningElementCommon - Reference: 2'-0" X 8'-0"; sets with these values: 2
Basic Wall:Wall_6.5":1623864 | Pset_OpeningElementCommon - Reference: Generic Models 63; sets with these values: 2
C_Single Door:3'-0" X 8'-0":1623476:1
C_Single Window:2'-6" X 2'-6":1623848:1
C_Single Window:2'-6" X 2'-6":1651531:1
C_Single Window:2'-6" X 2'-6":1654828:1
C_Window Guilotine:1'-10" X 3'-10":1649682:1
C_Double Window:5'-6" X 4'-8":1652023:1
C_Triple Window:8'-2" X 2'-4":1623486:1
C_Sliding Door Double Glass:5'-10" X 7'-8":1623487:1
C_Window Guilotine:2'-6" X 5'-10":1623489:1
Double Sliding Door:9'-4" X 7'-10":1623853:1
C_Single Door Glass:3'-0" X 8'-0":1623399:1
C_Atypical Window 6:12'-6" X 5'-10":1623398:1
C_Window Guilotine:2'-0" X 3'-10":1656494:1
C_Window Guilotine:2'-0" X 3'-10":1655540:1
C_Window Guilotine:2'-0" X 3'-10":1653680:1
C_Double Window Guilotine:4'-8" X 3'-10":1623395:1
C_Window Guilotine:2'-4" X 3'-10":1653142:1
C_Single Door:3'-0" X 8'-0":1623373:1
C_Double Window Guilotine:6'-4" X 5'-8":1623484:1
C_Single Door Glass:3'-0" X 8'-0":1623471:1
C_Single Door:2'-6" X 8'-0":1623393:1
C_Single Door:2'-0" X 8'-0":1623488:1
C_Single Door:3'-0" X 8'-0":1623400:1
C_Single Door:2'-4" X 8'-0":1623401:1
C_Single Door:2'-6" X 8'-0":1623370:1
C_Double Door Glass:4'-8" X 8'-0":1623472:1
C_Single Door:2'-4" X 8'-0":1623473:1
C_Single Door:2'-6" X 6'-8":1623378:1
C_Double Window:3'-8" X 3'-8":1763876:1
C_Double Door Glass:4'-8" X 8'-2":1623377:1
C_Single Window:5'-10" X 4'-10":1623382:1
C_Window Guilotine:2'-10" X 4'-10":1688913:1
C_Window Guilotine:2'-10" X 4'-10":1623381:1
C_Double Window:5'-0" X 4'-8":1623392:1
C_Double Window:3'-10" X 4'-0":1763479:1
C_Single Door:2'-4" X 8'-2":1623386:1
C_Single Door:2'-4" X 8'-2":1623384:1
C_Single Door:3'-0" X 8'-0":1623379:1
C_Single Door:2'-6" X 8'-0":1623380:1
C_Single Door:2'-6" X 8'-2":1623385:1
C_Single Door:2'-4" X 8'-2":1623387:1
C_Single Door:2'-6" X 8'-2":1623390:1
C_Single Door:2'-4" X 8'-2":1623388:1
C_Sliding Door Double:4'-10" X 8'-0":1623391:1
C_Single Window:2'-6" X 2'-6":1652445:1
C_Double Window Guilotine:6'-8" X 5'-10":1623402:1
C_Single Window:2'-6" X 2'-6":1652795:1
C_Single Door:2'-8" X 8'-0":1623371:1
C_Single Door:2'-6" X 8'-0":1623374:1
C_Single Door:2'-4" X 8'-0":1623375:1
C_Single Door:2'-4" X 8'-0":1623376:1
C_Single Door:2'-4" X 8'-0":1623474:1

# IfcOpeningElement: Recess (6)
In: First floor
Pset_OpeningElementCommon - sets with these values: 2
Name | Reference
Basic Wall:Wall_6.5":1623208 | Generic Models 19
Basic Wall:Wall_11":1623212 | Generic Models 20
Basic Wall:Wall_10":1623216 | 2'-0" X 8'-0"
Basic Wall:Wall_11":1623237 | Generic Models 1
Basic Wall:Wall_11":1623237 | Generic Models 54
Floor:Floor_13.5":1623341 | Generic Models 5

# IfcRailing: Railing:Railing_1.3 2 (3)
In: First floor
Classification: C2010400 Stair Handrails/Balustrades (Uniformat); Material: Default New Material
Pset_QuantityTakeOff - Reference: Railing_1.3 2
Pset_RailingCommon - IsExternal: no; Reference: Railing_1.3 2; Height: 3 ft
Name (Railing:Railing_1.3 2:...)
1826447
1826644
1826667

# IfcRailing: Railing:Railing_1.3 3, Railing:Railing_1.3 3:1826427
In: First floor
Classification: C2010400 Stair Handrails/Balustrades (Uniformat); Material: Default New Material
Pset_QuantityTakeOff - Reference: Railing_1.3 3
Pset_RailingCommon - IsExternal: no; Reference: Railing_1.3 3; Height: 3.16667 ft

# IfcRailing: Railing:Railing_4, Railing:Railing_4:1826361
In: First floor
Classification: C2010400 Stair Handrails/Balustrades (Uniformat); Material: Default New Material
Pset_QuantityTakeOff - Reference: Railing_4
Pset_RailingCommon - IsExternal: no; Reference: Railing_4; Height: 3 ft

# IfcRailing: Railing:Railing_4 2 (2)
In: First floor
Classification: C2010400 Stair Handrails/Balustrades (Uniformat); Material: Default New Material
Pset_QuantityTakeOff - Reference: Railing_4 2
Pset_RailingCommon - IsExternal: no; Reference: Railing_4 2; Height: 3.58333 ft
Name (Railing:Railing_4 2:...)
1826364
1826408

# IfcRailing: Railing:Railing_4 3, Railing:Railing_4 3:1826465
In: First floor
Classification: C2010400 Stair Handrails/Balustrades (Uniformat); Material: Default New Material
Pset_QuantityTakeOff - Reference: Railing_4 3
Pset_RailingCommon - IsExternal: no; Reference: Railing_4 3; Height: 2.83333 ft

# IfcSlab: Floor:Floor_13.5", Floor:Floor_13.5":1623341
In: First floor
Type - PredefinedType: FLOOR; Material: Default New Material 1.125 ft
Classification: B1010 Floor Construction (Uniformat)
Pset_QuantityTakeOff - Reference: Floor_13.5"; sets with these values: 2
Pset_SlabCommon - LoadBearing: no; IsExternal: no; PitchAngle: 0 deg; Reference: Floor_13.5"

# IfcSlab: Floor:Floor_6", Floor:Floor_6":1623299
In: First floor
Type - PredefinedType: FLOOR; Material: Default New Material 0.5 ft
Classification: B1010 Floor Construction (Uniformat)
Pset_QuantityTakeOff - Reference: Floor_6"; sets with these values: 2
Pset_SlabCommon - LoadBearing: no; Reference: Floor_6"; IsExternal: no; PitchAngle: 0 deg

# IfcStair: Assembled Stair:Stair_2018, Assembled Stair:Stair:1826337
In: First floor
Classification: C Interiors (Uniformat)
Pset_QuantityTakeOff - Reference: Stair_2018
Pset_StairCommon - IsExternal: no; Reference: Stair_2018; NumberOfRiser: 16; NumberOfTreads: 16; RiserHeight: 0.627604 ft; TreadLength: 1 ft

# IfcStairFlight: Non-Monolithic Run:1" Tread 1" Nosing 1/4" Riser 2, Assembled Stair:Stair:1826337 Run 1
In: First floor
Type - Pset_StairFlightCommon - NosingLength: 0.0833333 ft
NumberOfRiser: 16; NumberOfTreads: 16; RiserHeight: 0.627604 ft; TreadLength: 1 ft; Material: Default New Material
Pset_QuantityTakeOff - Reference: 1" Tread 1" Nosing 1/4" Riser 2
Pset_StairFlightCommon - Reference: 1" Tread 1" Nosing 1/4" Riser 2; NumberOfRiser: 16; NumberOfTreads: 16; RiserHeight: 0.627604 ft; TreadLength: 1 ft; TreadLengthAtOffset: 1 ft; TreadLengthAtInnerSide: 1 ft

# IfcWall: Basic Wall:Wall Border_T1, Basic Wall:Wall Border_T1:1623804
In: First floor
Type - PredefinedType: STANDARD; Material: Default New Material 0.0416667 ft
Classification: B2010 Exterior Walls (Uniformat)
Pset_QuantityTakeOff - Reference: Wall Border_T1; sets with these values: 2
Pset_WallCommon - IsExternal: yes; ExtendToStructure: no; LoadBearing: no; Reference: Wall Border_T1

# IfcWall: Basic Wall:Wall_1' 8 1/2", Basic Wall:Wall_1' 8 1/2":1623272
In: First floor
Type - PredefinedType: STANDARD; Material: Default New Material 1.70833 ft
Pset_QuantityTakeOff - Reference: Wall_1' 8 1/2"; sets with these values: 2
Pset_WallCommon - IsExternal: yes; ExtendToStructure: no; LoadBearing: no; Reference: Wall_1' 8 1/2"

# IfcWall: Basic Wall:Wall_1'3", Basic Wall:Wall_1'3":1623257
In: First floor
Type - PredefinedType: STANDARD; Material: Default New Material 1.25 ft
Pset_QuantityTakeOff - Reference: Wall_1'3"; sets with these values: 2
Pset_WallCommon - IsExternal: yes; ExtendToStructure: no; LoadBearing: no; Reference: Wall_1'3"

# IfcWall: Basic Wall:Wall_4.5" (4)
In: First floor
Type - PredefinedType: STANDARD; Material: Default New Material 0.375 ft
Classification: B2010 Exterior Walls (Uniformat)
Pset_QuantityTakeOff - Reference: Wall_4.5"; sets with these values: 2
Pset_WallCommon - IsExternal: yes; ExtendToStructure: no; LoadBearing: no; Reference: Wall_4.5"
Name (Basic Wall:Wall_4.5":...)
1623205
1623233
1623238
1623249

# IfcWall: Basic Wall:Wall_6.5" (2)
In: First floor
Type - PredefinedType: STANDARD; Material: Default New Material 0.541667 ft
Classification: B2010 Exterior Walls (Uniformat)
Pset_QuantityTakeOff - Reference: Wall_6.5"; sets with these values: 2
Pset_WallCommon - Reference: Wall_6.5"; IsExternal: yes; ExtendToStructure: no; LoadBearing: no
Name (Basic Wall:Wall_6.5":...)
1623228
1623235

# IfcWall: Basic Wall:Wall_9.5", Basic Wall:Wall_9.5":1623234
In: First floor
Type - PredefinedType: STANDARD; Material: Default New Material 0.791667 ft
Classification: B2010 Exterior Walls (Uniformat)
Pset_QuantityTakeOff - Reference: Wall_9.5"; sets with these values: 2
Pset_WallCommon - IsExternal: yes; ExtendToStructure: no; LoadBearing: no; Reference: Wall_9.5"

# IfcWallStandardCase: Basic Wall:Wall Border_T1 (256)
In: First floor
Type - PredefinedType: STANDARD; Material: Default New Material 0.0416667 ft
Classification: B2010 Exterior Walls (Uniformat)
Pset_QuantityTakeOff - Reference: Wall Border_T1; sets with these values: 2
Pset_WallCommon - IsExternal: yes; ExtendToStructure: no; LoadBearing: no; Reference: Wall Border_T1
Name (Basic Wall:Wall Border_T1:...)
1623404
1623405
1623406
1623407
1623408
1623409
1623410
1623411
1623412
1623413
1623414
1623415
1623416
1623417
1623418
1623419
1623420
1623421
1623422
1623423
1623424
1623425
1623426
1623427
1623428
1623429
1623430
1623431
1623432
1623433
1623434
1623435
1623436
1623437
1623438
1623439
1623440
1623441
1623442
1623443
1623444
1623449
1623450
1623451
1623452
1623453
1623454
1623455
1623456
1623457
1623458
1623459
1623460
1623461
1623462
1623463
1623464
1623465
1623467
1623468
1623469
1623477
1623478
1623479
1623480
1623481
1623482
1623483
1623490
1623505
1623506
1623507
1623508
1623509
1623510
1623511
1623512
1623513
1623514
1623515
1623516
1623517
1623518
1623519
1623520
1623521
1623522
1623523
1623524
1623525
1623526
1623527
1623560
1623561
1623562
1623563
1623564
1623565
1623566
1623567
1623568
1623569
1623570
1623571
1623572
1623579
1623580
1623581
1623582
1623583
1623584
1623585
1623586
1623587
1623588
1623589
1623590
1623602
1623603
1623604
1623605
1623606
1623607
1623608
1623609
1623610
1623611
1623623
1623624
1623625
1623626
1623627
1623628
1623629
1623630
1623631
1623632
1623633
1623634
1623635
1623636
1623637
1623638
1623639
1623649
1623650
1623651
1623652
1623653
1623654
1623655
1623656
1623657
1623658
1623659
1623729
1623730
1623731
1623732
1623733
1623734
1623735
1623736
1623737
1623738
1623739
1623740
1623741
1623742
1623743
1623744
1623745
1623746
1623747
1623748
1623749
1623750
1623751
1623752
1623753
1623754
1623755
1623756
1623757
1623758
1623759
1623761
1623762
1623763
1623764
1623765
1623766
1623767
1623768
1623769
1623770
1623771
1623772
1623773
1623774
1623775
1623776
1623777
1623778
1623779
1623780
1623781
1623782
1623783
1623784
1623785
1623786
1623787
1623789
1623790
1623791
1623792
1623793
1623794
1623795
1623796
1623797
1623798
1623799
1623800
1623802
1623803
1623805
1623806
1623807
1623808
1623809
1623810
1623811
1623812
1623813
1623814
1623815
1623816
1623819
1623820
1623821
1623822
1623823
1623842
1623933
1904057
1904125
1904173
1909334
1909423
1909518
2013327
2013328
2013329
2013330

# IfcWallStandardCase: Basic Wall:Wall_1' 1 3/4", Basic Wall:Wall_1' 1 3/4":1623259
In: First floor
Type - PredefinedType: STANDARD; Material: Default New Material 1.14583 ft
Pset_QuantityTakeOff - Reference: Wall_1' 1 3/4"; sets with these values: 2
Pset_WallCommon - IsExternal: yes; ExtendToStructure: no; LoadBearing: no; Reference: Wall_1' 1 3/4"

# IfcWallStandardCase: Basic Wall:Wall_1' 10", Basic Wall:Wall_1' 10":1623271
In: First floor
Type - PredefinedType: STANDARD; Material: Default New Material 1.83333 ft
Pset_QuantityTakeOff - Reference: Wall_1' 10"; sets with these values: 2
Pset_WallCommon - IsExternal: yes; ExtendToStructure: no; LoadBearing: no; Reference: Wall_1' 10"

# IfcWallStandardCase: Basic Wall:Wall_1' 2 1/2", Basic Wall:Wall_1' 2 1/2":1623269
In: First floor
Type - PredefinedType: STANDARD; Material: Default New Material 1.20833 ft
Pset_QuantityTakeOff - Reference: Wall_1' 2 1/2"; sets with these values: 2
Pset_WallCommon - IsExternal: yes; ExtendToStructure: no; LoadBearing: no; Reference: Wall_1' 2 1/2"

# IfcWallStandardCase: Basic Wall:Wall_1' 3 1/2" (2)
In: First floor
Type - PredefinedType: STANDARD; Material: Default New Material 1.29167 ft
Pset_QuantityTakeOff - Reference: Wall_1' 3 1/2"; sets with these values: 2
Pset_WallCommon - IsExternal: yes; ExtendToStructure: no; LoadBearing: no; Reference: Wall_1' 3 1/2"
Name (Basic Wall:Wall_1' 3 1/2":...)
1623296
1894544

# IfcWallStandardCase: Basic Wall:Wall_1' 3/4", Basic Wall:Wall_1' 3/4":1623270
In: First floor
Type - PredefinedType: STANDARD; Material: Default New Material 1.0625 ft
Pset_QuantityTakeOff - Reference: Wall_1' 3/4"; sets with these values: 2
Pset_WallCommon - IsExternal: yes; ExtendToStructure: no; LoadBearing: no; Reference: Wall_1' 3/4"

# IfcWallStandardCase: Basic Wall:Wall_1'1/2" (2)
In: First floor
Type - PredefinedType: STANDARD; Material: Default New Material 1.04167 ft
Pset_QuantityTakeOff - Reference: Wall_1'1/2"; sets with these values: 2
Pset_WallCommon - IsExternal: yes; ExtendToStructure: no; LoadBearing: no; Reference: Wall_1'1/2"
Name (Basic Wall:Wall_1'1/2":...)
1623254
1623268

# IfcWallStandardCase: Basic Wall:Wall_1'2", Basic Wall:Wall_1'2":1623256
In: First floor
Type - PredefinedType: STANDARD; Material: Default New Material 1.16667 ft
Pset_QuantityTakeOff - Reference: Wall_1'2"; sets with these values: 2
Pset_WallCommon - IsExternal: yes; ExtendToStructure: no; LoadBearing: no; Reference: Wall_1'2"

# IfcWallStandardCase: Basic Wall:Wall_1'3", Basic Wall:Wall_1'3":1623255
In: First floor
Type - PredefinedType: STANDARD; Material: Default New Material 1.25 ft
Pset_QuantityTakeOff - Reference: Wall_1'3"; sets with these values: 2
Pset_WallCommon - IsExternal: yes; ExtendToStructure: no; LoadBearing: no; Reference: Wall_1'3"

# IfcWallStandardCase: Basic Wall:Wall_1'6", Basic Wall:Wall_1'6":1623262
In: First floor
Type - PredefinedType: STANDARD; Material: Default New Material 1.5 ft
Classification: B2010 Exterior Walls (Uniformat)
Pset_QuantityTakeOff - Reference: Wall_1'6"; sets with these values: 2
Pset_WallCommon - IsExternal: yes; ExtendToStructure: no; LoadBearing: no; Reference: Wall_1'6"

# IfcWallStandardCase: Basic Wall:Wall_1'7", Basic Wall:Wall_1'7":1623281
In: First floor
Type - PredefinedType: STANDARD; Material: Default New Material 1.58333 ft
Pset_QuantityTakeOff - Reference: Wall_1'7"; sets with these values: 2
Pset_WallCommon - IsExternal: yes; ExtendToStructure: no; LoadBearing: no; Reference: Wall_1'7"

# IfcWallStandardCase: Basic Wall:Wall_10" (3)
In: First floor
Type - PredefinedType: STANDARD; Material: Default New Material 0.833333 ft
Classification: B2010 Exterior Walls (Uniformat)
Pset_QuantityTakeOff - Reference: Wall_10"; sets with these values: 2
Pset_WallCommon - IsExternal: yes; ExtendToStructure: no; LoadBearing: no; Reference: Wall_10"
Name (Basic Wall:Wall_10":...)
1623216
1623264
1623287

# IfcWallStandardCase: Basic Wall:Wall_10.5", Basic Wall:Wall_10.5":1623266
In: First floor
Type - PredefinedType: STANDARD; Material: Default New Material 0.875 ft
Classification: B2010 Exterior Walls (Uniformat)
Pset_QuantityTakeOff - Reference: Wall_10.5"; sets with these values: 2
Pset_WallCommon - IsExternal: yes; ExtendToStructure: no; LoadBearing: no; Reference: Wall_10.5"

# IfcWallStandardCase: Basic Wall:Wall_11" (2)
In: First floor
Type - PredefinedType: STANDARD; Material: Default New Material 0.916667 ft
Classification: B2010 Exterior Walls (Uniformat)
Pset_QuantityTakeOff - Reference: Wall_11"; sets with these values: 2
Pset_WallCommon - IsExternal: yes; ExtendToStructure: no; LoadBearing: no; Reference: Wall_11"
Name (Basic Wall:Wall_11":...)
1623212
1623237

# IfcWallStandardCase: Basic Wall:Wall_17", Basic Wall:Wall_17":1623243
In: First floor
Type - PredefinedType: STANDARD; Material: Default New Material 1.41667 ft
Classification: B2010 Exterior Walls (Uniformat)
Pset_QuantityTakeOff - Reference: Wall_17"; sets with these values: 2
Pset_WallCommon - IsExternal: yes; ExtendToStructure: no; LoadBearing: no; Reference: Wall_17"

# IfcWallStandardCase: Basic Wall:Wall_3.5", Basic Wall:Wall_3.5":1623231
In: First floor
Type - PredefinedType: STANDARD; Material: Default New Material 0.291667 ft
Classification: B2010 Exterior Walls (Uniformat)
Pset_QuantityTakeOff - Reference: Wall_3.5"; sets with these values: 2
Pset_WallCommon - IsExternal: yes; ExtendToStructure: no; LoadBearing: no; Reference: Wall_3.5"

# IfcWallStandardCase: Basic Wall:Wall_4.5" (34)
In: First floor
Type - PredefinedType: STANDARD; Material: Default New Material 0.375 ft
Classification: B2010 Exterior Walls (Uniformat)
Pset_QuantityTakeOff - Reference: Wall_4.5"; sets with these values: 2
Pset_WallCommon - IsExternal: yes; ExtendToStructure: no; LoadBearing: no; Reference: Wall_4.5"
Name (Basic Wall:Wall_4.5":...)
1623201
1623206
1623207
1623209
1623218
1623219
1623220
1623221
1623226
1623232
1623239
1623241
1623248
1623253
1623274
1623275
1623276
1623277
1623278
1623279
1623280
1623283
1623284
1623285
1623288
1623289
1623292
1623293
1623294
1623295
1623491
1623492
1623493
1999604

# IfcWallStandardCase: Basic Wall:Wall_5", Basic Wall:Wall_5":1623265
In: First floor
Type - PredefinedType: STANDARD; Material: Default New Material 0.416667 ft
Classification: B2010 Exterior Walls (Uniformat)
Pset_QuantityTakeOff - Reference: Wall_5"; sets with these values: 2
Pset_WallCommon - IsExternal: yes; ExtendToStructure: no; LoadBearing: no; Reference: Wall_5"

# IfcWallStandardCase: Basic Wall:Wall_5.5" (6)
In: First floor
Type - PredefinedType: STANDARD; Material: Default New Material 0.458333 ft
Classification: B2010 Exterior Walls (Uniformat)
Pset_QuantityTakeOff - Reference: Wall_5.5"; sets with these values: 2
Pset_WallCommon - IsExternal: yes; ExtendToStructure: no; LoadBearing: no; Reference: Wall_5.5"
Name (Basic Wall:Wall_5.5":...)
1623202
1623213
1623230
1623246
1623247
1623290

# IfcWallStandardCase: Basic Wall:Wall_6", Basic Wall:Wall_6":1623286
In: First floor
Type - PredefinedType: STANDARD; Material: Default New Material 0.5 ft
Pset_QuantityTakeOff - Reference: Wall_6"; sets with these values: 2
Pset_WallCommon - IsExternal: yes; ExtendToStructure: no; LoadBearing: no; Reference: Wall_6"

# IfcWallStandardCase: Basic Wall:Wall_6.5" (28)
In: First floor
Type - PredefinedType: STANDARD; Material: Default New Material 0.541667 ft
Classification: B2010 Exterior Walls (Uniformat)
Pset_QuantityTakeOff - Reference: Wall_6.5"; sets with these values: 2
Pset_WallCommon - Reference: Wall_6.5"; IsExternal: yes; ExtendToStructure: no; LoadBearing: no
Name (Basic Wall:Wall_6.5":...)
1623185
1623186
1623188
1623189
1623190
1623191
1623193
1623194
1623195
1623196
1623197
1623198
1623203
1623204
1623208
1623210
1623215
1623222
1623223
1623227
1623250
1623252
1623260
1623261
1623273
1623291
1623368
1623864

# IfcWallStandardCase: Basic Wall:Wall_6.75", Basic Wall:Wall_6.75":1623245
In: First floor
Type - PredefinedType: STANDARD; Material: Default New Material 0.5625 ft
Classification: B2010 Exterior Walls (Uniformat)
Pset_QuantityTakeOff - Reference: Wall_6.75"; sets with these values: 2
Pset_WallCommon - IsExternal: yes; ExtendToStructure: no; LoadBearing: no; Reference: Wall_6.75"

# IfcWallStandardCase: Basic Wall:Wall_7", Basic Wall:Wall_7":1623217
In: First floor
Type - PredefinedType: STANDARD; Material: Default New Material 0.583333 ft
Classification: B2010 Exterior Walls (Uniformat)
Pset_QuantityTakeOff - Reference: Wall_7"; sets with these values: 2
Pset_WallCommon - IsExternal: yes; ExtendToStructure: no; LoadBearing: no; Reference: Wall_7"

# IfcWallStandardCase: Basic Wall:Wall_7.5" (3)
In: First floor
Type - PredefinedType: STANDARD; Material: Default New Material 0.625 ft
Classification: B2010 Exterior Walls (Uniformat)
Pset_QuantityTakeOff - Reference: Wall_7.5"; sets with these values: 2
Pset_WallCommon - IsExternal: yes; ExtendToStructure: no; LoadBearing: no; Reference: Wall_7.5"
Name (Basic Wall:Wall_7.5":...)
1623200
1623229
1623258

# IfcWallStandardCase: Basic Wall:Wall_8" (8)
In: First floor
Type - PredefinedType: STANDARD; Material: Default New Material 0.666667 ft
Classification: B2010 Exterior Walls (Uniformat)
Pset_QuantityTakeOff - Reference: Wall_8"; sets with these values: 2
Pset_WallCommon - IsExternal: yes; ExtendToStructure: no; LoadBearing: no; Reference: Wall_8"
Name (Basic Wall:Wall_8":...)
1623187
1623211
1623214
1623224
1623225
1623242
1623263
2014976

# IfcWallStandardCase: Basic Wall:Wall_8.5" (6)
In: First floor
Type - PredefinedType: STANDARD; Material: Default New Material 0.708333 ft
Classification: B2010 Exterior Walls (Uniformat)
Pset_QuantityTakeOff - Reference: Wall_8.5"; sets with these values: 2
Pset_WallCommon - IsExternal: yes; ExtendToStructure: no; LoadBearing: no; Reference: Wall_8.5"
Name (Basic Wall:Wall_8.5":...)
1623192
1623199
1623236
1623240
1623267
2006563

# IfcWallStandardCase: Basic Wall:Wall_9", Basic Wall:Wall_9":1623251
In: First floor
Type - PredefinedType: STANDARD; Material: Default New Material 0.75 ft
Classification: B2010 Exterior Walls (Uniformat)
Pset_QuantityTakeOff - Reference: Wall_9"; sets with these values: 2
Pset_WallCommon - IsExternal: yes; ExtendToStructure: no; LoadBearing: no; Reference: Wall_9"

# IfcWindow: C_Atypical Window 6:12'-6" X 5'-10", C_Atypical Window 6:12'-6" X 5'-10":1623398
In: First floor
Type - ParameterTakesPrecedence: no; Sizeable: no; Material: Default New Material, Glass
OverallHeight: 6 ft; OverallWidth: 12.6667 ft
Pset_QuantityTakeOff - Reference: 12'-6" X 5'-10"
Pset_WindowCommon - IsExternal: yes; Reference: 12'-6" X 5'-10"

# IfcWindow: C_Double Window Guilotine:4'-8" X 3'-10", C_Double Window Guilotine:4'-8" X 3'-10":1623395
In: First floor
Type - ParameterTakesPrecedence: no; Sizeable: no; Material: Default New Material, Glass
OverallHeight: 4 ft; OverallWidth: 4.83333 ft
Pset_QuantityTakeOff - Reference: 4'-8" X 3'-10"
Pset_WindowCommon - IsExternal: yes; Reference: 4'-8" X 3'-10"

# IfcWindow: C_Double Window Guilotine:6'-4" X 5'-8", C_Double Window Guilotine:6'-4" X 5'-8":1623484
In: First floor
Type - ParameterTakesPrecedence: no; Sizeable: no; Material: Default New Material, Glass
OverallHeight: 5.83333 ft; OverallWidth: 6.5 ft
Pset_QuantityTakeOff - Reference: 6'-4" X 5'-8"
Pset_WindowCommon - IsExternal: yes; Reference: 6'-4" X 5'-8"

# IfcWindow: C_Double Window Guilotine:6'-8" X 5'-10", C_Double Window Guilotine:6'-8" X 5'-10":1623402
In: First floor
Type - ParameterTakesPrecedence: no; Sizeable: no; Material: Default New Material, Glass
OverallHeight: 6 ft; OverallWidth: 6.83333 ft
Pset_QuantityTakeOff - Reference: 6'-8" X 5'-10"
Pset_WindowCommon - IsExternal: yes; Reference: 6'-8" X 5'-10"

# IfcWindow: C_Double Window:3'-10" X 4'-0", C_Double Window:3'-10" X 4'-0":1763479
In: First floor
Type - ParameterTakesPrecedence: no; Sizeable: no; Material: Glass, Default New Material
OverallHeight: 4.16667 ft; OverallWidth: 4 ft
Pset_QuantityTakeOff - Reference: 3'-10" X 4'-0"
Pset_WindowCommon - IsExternal: yes; Reference: 3'-10" X 4'-0"

# IfcWindow: C_Double Window:3'-8" X 3'-8", C_Double Window:3'-8" X 3'-8":1763876
In: First floor
Type - ParameterTakesPrecedence: no; Sizeable: no; Material: Glass, Default New Material
OverallHeight: 3.83333 ft; OverallWidth: 3.83333 ft
Pset_QuantityTakeOff - Reference: 3'-8" X 3'-8"
Pset_WindowCommon - IsExternal: yes; Reference: 3'-8" X 3'-8"

# IfcWindow: C_Double Window:5'-0" X 4'-8", C_Double Window:5'-0" X 4'-8":1623392
In: First floor
Type - ParameterTakesPrecedence: no; Sizeable: no; Material: Default New Material, Glass
OverallHeight: 4.83333 ft; OverallWidth: 5.16667 ft
Pset_QuantityTakeOff - Reference: 5'-0" X 4'-8"
Pset_WindowCommon - IsExternal: yes; Reference: 5'-0" X 4'-8"
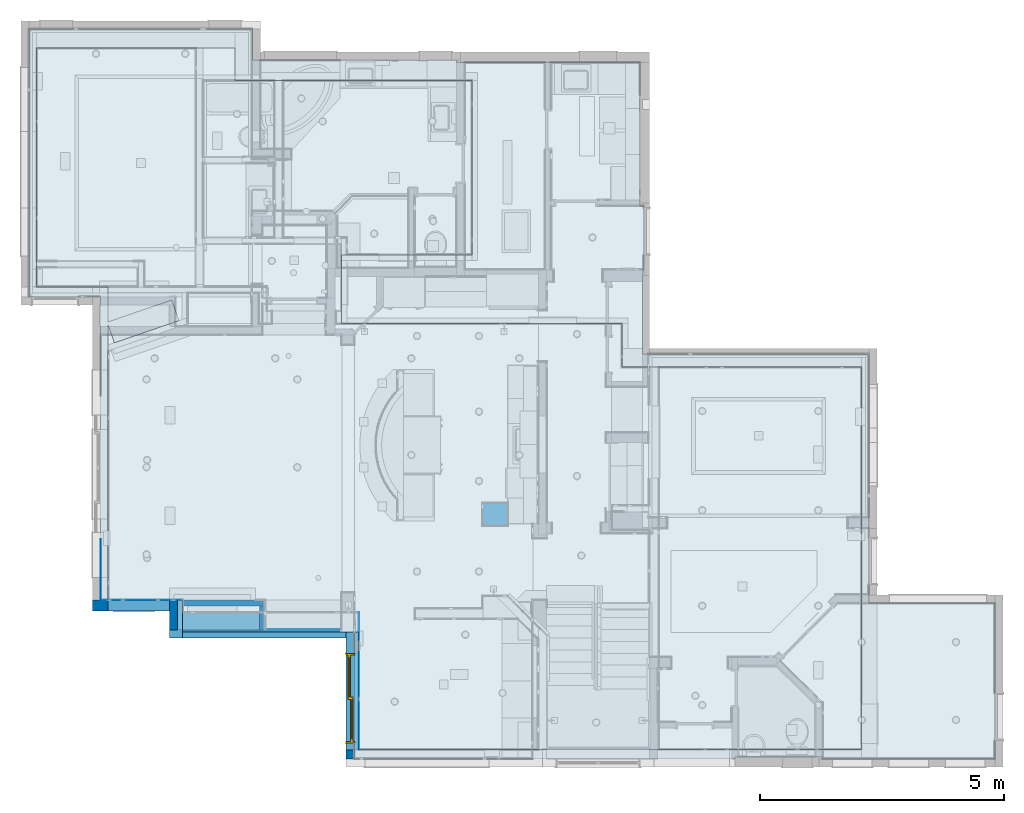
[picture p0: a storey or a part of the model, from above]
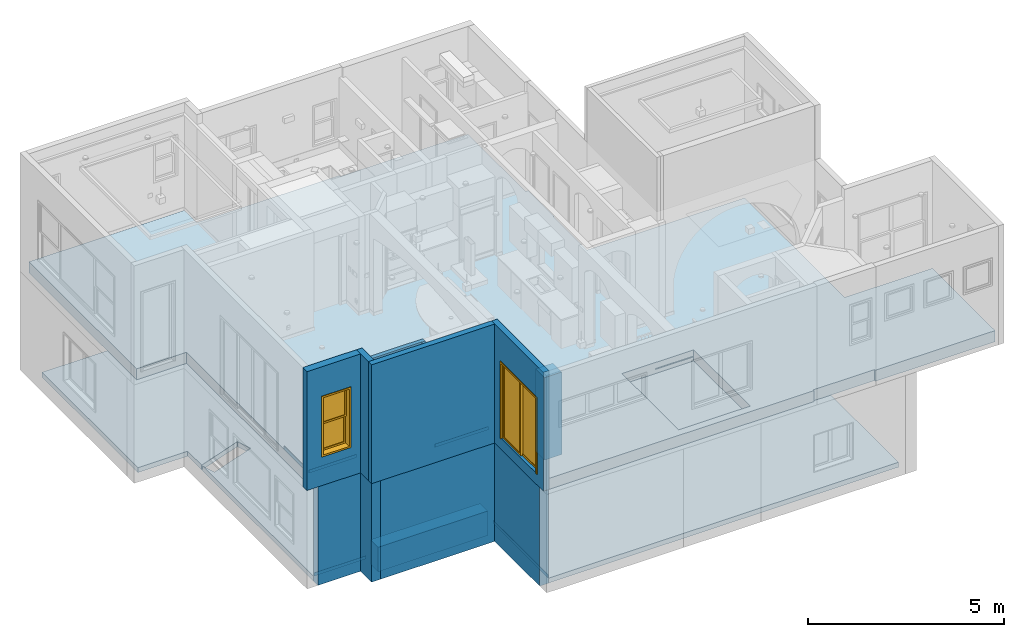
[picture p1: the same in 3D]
Properties of the parts of a building model (IFC2X3), part 2 of 2

# IfcWindow: C_Double Window:5'-6" X 4'-8", C_Double Window:5'-6" X 4'-8":1652023
In: First floor
Type - ParameterTakesPrecedence: no; Sizeable: no; Material: Default New Material, Glass
OverallHeight: 4.83333 ft; OverallWidth: 5.66667 ft
Pset_QuantityTakeOff - Reference: 5'-6" X 4'-8"
Pset_WindowCommon - IsExternal: yes; Reference: 5'-6" X 4'-8"

# IfcWindow: C_Single Window:2'-6" X 2'-6" (5)
In: First floor
Type - ParameterTakesPrecedence: no; Sizeable: no; Material: Default New Material, Glass
OverallHeight: 2.66667 ft; OverallWidth: 2.66667 ft
Pset_QuantityTakeOff - Reference: 2'-6" X 2'-6"
Pset_WindowCommon - IsExternal: yes; Reference: 2'-6" X 2'-6"
Name (C_Single Window:2'-6" X 2'-6":...)
1623848
1651531
1652445
1652795
1654828

# IfcWindow: C_Single Window:5'-10" X 4'-10", C_Single Window:5'-10" X 4'-10":1623382
In: First floor
Type - ParameterTakesPrecedence: no; Sizeable: no; Material: Glass, Default New Material
OverallHeight: 5 ft; OverallWidth: 6 ft
Pset_QuantityTakeOff - Reference: 5'-10" X 4'-10"
Pset_WindowCommon - IsExternal: yes; Reference: 5'-10" X 4'-10"

# IfcWindow: C_Triple Window:8'-2" X 2'-4", C_Triple Window:8'-2" X 2'-4":1623486
In: First floor
Type - ParameterTakesPrecedence: no; Sizeable: no; Material: Default New Material, Glass
OverallHeight: 2.5 ft; OverallWidth: 8.33333 ft
Pset_QuantityTakeOff - Reference: 8'-2" X 2'-4"
Pset_WindowCommon - IsExternal: yes; Reference: 8'-2" X 2'-4"

# IfcWindow: C_Window Guilotine:1'-10" X 3'-10", C_Window Guilotine:1'-10" X 3'-10":1649682
In: First floor
Type - ParameterTakesPrecedence: no; Sizeable: no; Material: Default New Material, Glass
OverallHeight: 4 ft; OverallWidth: 2 ft
Pset_QuantityTakeOff - Reference: 1'-10" X 3'-10"
Pset_WindowCommon - IsExternal: yes; Reference: 1'-10" X 3'-10"

# IfcWindow: C_Window Guilotine:2'-0" X 3'-10" (3)
In: First floor
Type - ParameterTakesPrecedence: no; Sizeable: no; Material: Default New Material, Glass
OverallHeight: 4 ft; OverallWidth: 2.16667 ft
Pset_QuantityTakeOff - Reference: 2'-0" X 3'-10"
Pset_WindowCommon - IsExternal: yes; Reference: 2'-0" X 3'-10"
Name (C_Window Guilotine:2'-0" X 3'-10":...)
1653680
1655540
1656494

# IfcWindow: C_Window Guilotine:2'-10" X 4'-10" (2)
In: First floor
Type - ParameterTakesPrecedence: no; Sizeable: no; Material: Default New Material, Glass
OverallHeight: 5 ft; OverallWidth: 3 ft
Pset_QuantityTakeOff - Reference: 2'-10" X 4'-10"
Pset_WindowCommon - IsExternal: yes; Reference: 2'-10" X 4'-10"
Name (C_Window Guilotine:2'-10" X 4'-10":...)
1623381
1688913

# IfcWindow: C_Window Guilotine:2'-4" X 3'-10", C_Window Guilotine:2'-4" X 3'-10":1653142
In: First floor
Type - ParameterTakesPrecedence: no; Sizeable: no; Material: Default New Material, Glass
OverallHeight: 4 ft; OverallWidth: 2.5 ft
Pset_QuantityTakeOff - Reference: 2'-4" X 3'-10"
Pset_WindowCommon - IsExternal: yes; Reference: 2'-4" X 3'-10"

# IfcWindow: C_Window Guilotine:2'-6" X 5'-10", C_Window Guilotine:2'-6" X 5'-10":1623489
In: First floor
Type - ParameterTakesPrecedence: no; Sizeable: no; Material: Default New Material, Glass
OverallHeight: 6 ft; OverallWidth: 2.66667 ft
Pset_QuantityTakeOff - Reference: 2'-6" X 5'-10"
Pset_WindowCommon - IsExternal: yes; Reference: 2'-6" X 5'-10"
